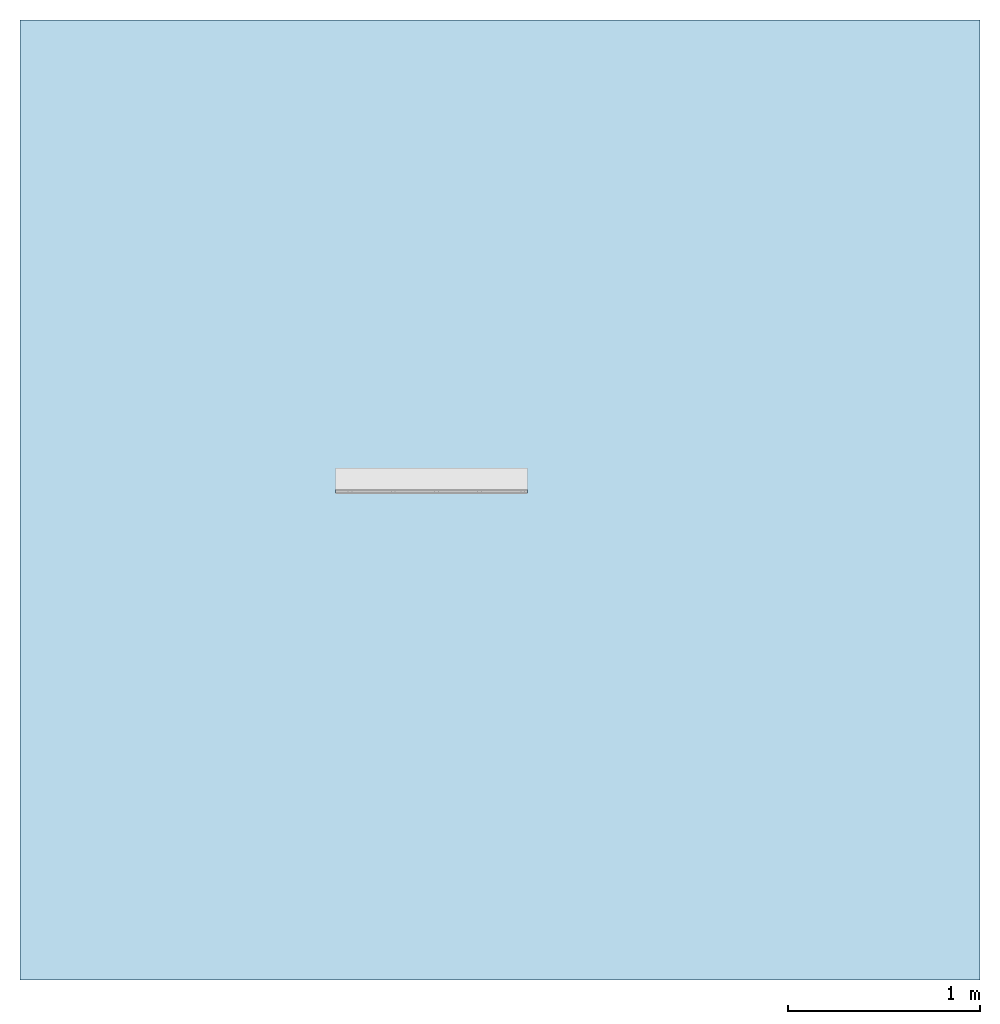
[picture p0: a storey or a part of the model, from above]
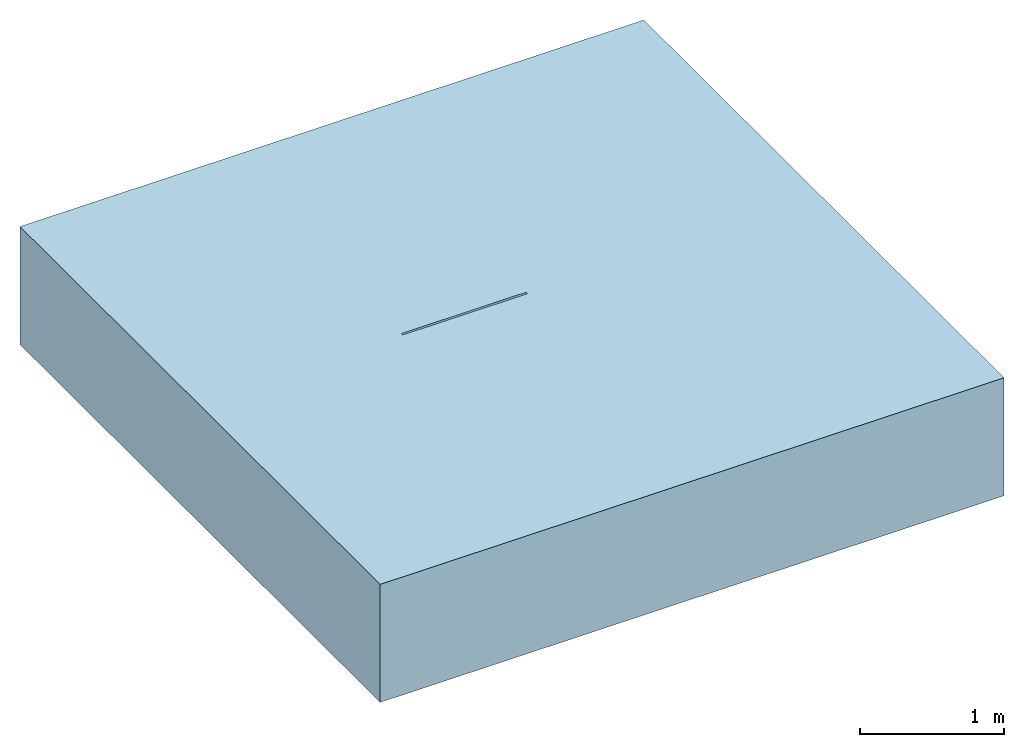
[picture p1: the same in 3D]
Properties of the parts of a building model (IFC2X3)

# File
Description: ViewDefinition [CoordinationView]
File name: 23005 - No 5 Sloping Channel - 1000mm LG - Invert Depth 150-155mm.ifc
Time: 2013-10-31T17:22:44
Written by: Autodesk Revit 2013
Made in: 20120221_2030(x64)

# IfcProject, Project Number
LongName: Project Name; Phase: Project Status

# IfcSite, Default
RefLatitude: 42, 21, 30, 344238; RefLongitude: -71, -3, -35, -194702; RefElevation: 0 mm

# IfcBuilding
Pset_BuildingCommon - NumberOfStoreys: 1
Other - Client Name: Owner; Project Address: ## Street City, State Zip; Project Issue Date: Issue Date; Project Name: Project Name; Project Status: Project Status; Project Number: Project Number

# IfcBuildingStorey, Level 1
LongName: Level 1; Elevation: 0 mm
Constraints - Elevation Base: 0; Elevation: 0 mm
Graphics - Symbol at End 1 Default: no; Symbol: M_Level Head - Circle: M_Level Head - Circle; Color: 0; Line Weight: 1; Symbol at End 2 Default: yes; Line Pattern: Center
Identity Data - Structural: no; Building Story: yes; Name: Level 1
Dimensions - Computation Height: 0 mm

# IfcBuildingElementProxy: 23005 - No 5 Sloping Channel - 1000mm LG - Invert Depth 150/155mm, Civil-Drainage-Channel-ACO-MultiDrain-M100D-Brickslot-Channel-System:23005 - No 5 Sloping Channel - 1000mm LG - Invert Depth 150/155mm:23005 - No 5 Sloping Channel - 1000mm LG - Invert Depth 150/155mm:196059
In: Level 1
Material: Steel, Galvanized, Vienite® Synthetic Resin Concrete
Dimensions - EndCap Position: 1000 mm; Brickslot Void Length: 1000 mm; Custom_Void_length: 0 mm; Volume: 9376288 mm3; Brickslot Access Unit Void Bottom Depth: -6605 mm; Brickslot Void Depth: 0 mm; FloorCut_Length: -1000 mm; Length: 1000 mm; Brickslot Access Unit Void Depth: -6500 mm; InvDepth: 80 mm; SlopingInvertDepth: 100 mm; Depth: 150 mm; GratingLength: -1000 mm; SlopingOverallDepth: 170 mm; EndCap_Height: 175 mm; ShallowInvDepth: 55 mm; SlopingEndOverallDepth: 175 mm; Length Drain: -1000 mm; SlopingEndInvertDepth: 105 mm; FloorCut_Width: 135 mm; Brickslot Access Unit Floor Cut Length: 500 mm; Floor Cut Gap: 105 mm; ShallowOverallDepth: 75 mm; FloorCut_Depth: 175 mm; Access_Custom_Void_Length: 0 mm
Construction - 23462_Load Class C250_Brickslot Access Unit_Galvanised Steel_500mm Long: no; 23465_Load Class D400_Brickslot Grating_Galvanized Steel_1000mm Long: yes; 23404_Universal Endcap (Male End): no; 23460_Load Class C250_Brickslot Grating_Galvanized Steel_1000mm Long: no; 23467_Load Class D400_Brickslot Access Unit_Galvanised Steel_500mm Long: no; 23466_Load Class D400_Brickslot Grating_Galvanized Steel_500mm Long: no; 23404_Universal Endcap (Female End): no; 23461_Load Class C250_Brickslot Grating_Galvanized Steel_500mm Long: no; Constant Depth Channel: no; Constant Depth Junction Channel: no; Shallow Depth Channel with seal: no; Sloping Channel: yes; Shallow Depth Channel: no; 23410_Sump Unit: no
Phasing - Phase Created: New Construction
Constraints - Moves With Nearby Elements: no; Level: Level: Level 1
Pset_BuildingElementProxyCommon - Reference: 23005 - No 5 Sloping Channel - 1000mm LG - Invert Depth 150/155mm
Data - Concrete Surround Volume - Load Class D 400 - Concrete Pavement: N/A; Product Standard: BS EN 1433:2002, CE marked; Concrete Surround Volume - Load Class B 125 - C 250 - Concrete Pavement: N/A; Installation - Concrete Grade: Refer to brochure; Pre-formed Outlet Ø: N/A; Load Class: A 15 - D 400; Invert Depth: 150mm/155mm; Channel C.S.A: N/A; Concrete Surround Volume - Load Class A 15 - Concrete Pavement: N/A; Hydraulic Performance: http://www.aco.co.uk/download.php?id=173; Product Dimensions: 1000mm x 135mm x 170mm/175mm (LxWxH); ACO Hydraulic Design Software: http://www.acodesign.co.uk; Product Weight: 14.7 Kg
General - TagNumber: 0; SerialNumber: 0
Materials and Finishes - Edge Rail Finish: Pre-galvanised; Channel Colour: Brown; Edge Rail Material: Steel; Edge Rail Colour: Silver; Channel Material: Vienite® Synthetic Resin Concrete
Identity Data - Cost: 0; Fax: +44 (0)1462 815895; e-mail Sales: customersupport@aco.co.uk; Product Page URL: http://www.aco.co.uk/product_detail.php?id=58; Installation guidelines: http://www.aco.co.uk/download.php?id=173; Address: ACO Business Park, Hitchin Road, Shefford, Bedfordshire, United Kingdom SG17 5TE; OmniClass Title: Rainwater Removal; Watermark 1: This file is the property of ACO Technologies PLC; URL: www.aco.co.uk; Watermarked With: BIM Manager Premium Suite; Product brochure: http://www.aco.co.uk/download.php?id=173; Price: POA - contact ACO; Product Code: 23005; Maintenance guidelines: http://www.aco.co.uk/download.php?id=173; Assembly Code: D2040; Model: ACO MultiDrain MD Brickslot- M100D; Telephone: +44 (0)1462 816666; OmniClass Number: 23.70.50.24; e-mail Technical: technical@aco.co.uk; Type Comments: ACO MultiDrain M100D No 5 Sloping Channel 1000mm Long; Assembly Description: Rain Water Drainage; Manufacturer: ACO Technologies plc - ACO Water Management Division; Watermark 2: This file is water marked and users are prohibited to reproduce, adapt, distribute this information; Model Description: Channel drainage system
Green Building Properties - Channel Recyclable: Fully recyclable; Edge Rail Recyclable: Fully recyclable; Channel Recycled Material Content: 20% minimum; Edge Rail Recycled Material Content: Between 40% - 90%
Other - Watermarked By: www.aco.co.uk; Created By: www.aco.co.uk; Revision: 1
Model Properties - Brickslot Access Unit Product code 23467: Load Class D400 - Brickslot Access Unit Galvanised Steel - 500mm long x 105mm high - 10mm Slot - Intake area - 10000mm²/m - 6.4 Kg; Brickslot Grating Product code 23466: Load Class D400 - Brickslot Galvanised Steel - 500mm long x 105mm high - 10mm Slot - Intake area - 10000mm²/m - 3.3 Kg; End Cap Product code 23404: No 306 Universal End Cap - 135mm wide x 300mm long - Spigot Ø110mm x 50mm long - Silver - Polypropylene - 0.16kg; Brickslot Grating Product code 23460: Load Class C250 - Brickslot Galvanised Steel - 1000mm long x 105mm high - 10mm Slot - Intake area - 10000mm²/m - 6.6 Kg; Brickslot Access Unit Product code 23462: Load Class C250 - Brickslot Access Unit Galvanised Steel - 500mm long x 105mm high - 10mm Slot - Intake area - 10000mm²/m - 6.4 Kg; Brickslot Grating Product code 23461: Load Class C250 - Brickslot Galvanised Steel - 500mm long x 105mm high - 10mm Slot - Intake area - 10000mm²/m -3.3 Kg; Brickslot Grating Product code 23465: Load Class D400 - Brickslot Galvanised Steel - 1000mm long x 105mm high - 10mm Slot - Intake area - 10000mm²/m - 6.6 Kg

# IfcOpeningElement: Recess (2)
In: Level 1
Constraints - Level: Level: Level 1; Related to Mass: no; Room Bounding: yes; Height Offset From Level: 0 mm
Structural - Enable Analytical Model: no; Structural: no
Phasing - Phase Created: New Construction
Dimensions - Area: 25000000 mm2; Perimeter: 20000 mm; Volume: 24974485000 mm3; Thickness: 1000 mm
Graphics - Coarse Scale Fill Color: 0
Analytical Properties - Roughness: 1; Heat Transfer Coefficient (U): 0.837; Thermal Resistance (R): 1.19474; Thermal mass: 1359800; Absorptance: 0.1
Materials and Finishes - Structural Material: Earth
Construction - Default Thickness: 1000 mm; Function: 0

# IfcSlab: Floor:Generic Floor - 1000mm, Floor:Generic Floor - 1000mm:193825
In: Level 1
PredefinedType: FLOOR; Material: Earth 1000 mm
Constraints - Level: Level: Level 1; Related to Mass: no; Room Bounding: yes; Height Offset From Level: 0 mm
Structural - Enable Analytical Model: no; Structural: no
Phasing - Phase Created: New Construction
Dimensions - Area: 25000000 mm2; Perimeter: 20000 mm; Volume: 24974485000 mm3; Thickness: 1000 mm
Pset_SlabCommon - Reference: Generic Floor - 1000mm; IsExternal: no; LoadBearing: yes
Graphics - Coarse Scale Fill Color: 0
Analytical Properties - Roughness: 1; Heat Transfer Coefficient (U): 0.837; Thermal Resistance (R): 1.19474; Thermal mass: 1359800; Absorptance: 0.1
Materials and Finishes - Structural Material: Earth
Construction - Default Thickness: 1000 mm; Function: 0
